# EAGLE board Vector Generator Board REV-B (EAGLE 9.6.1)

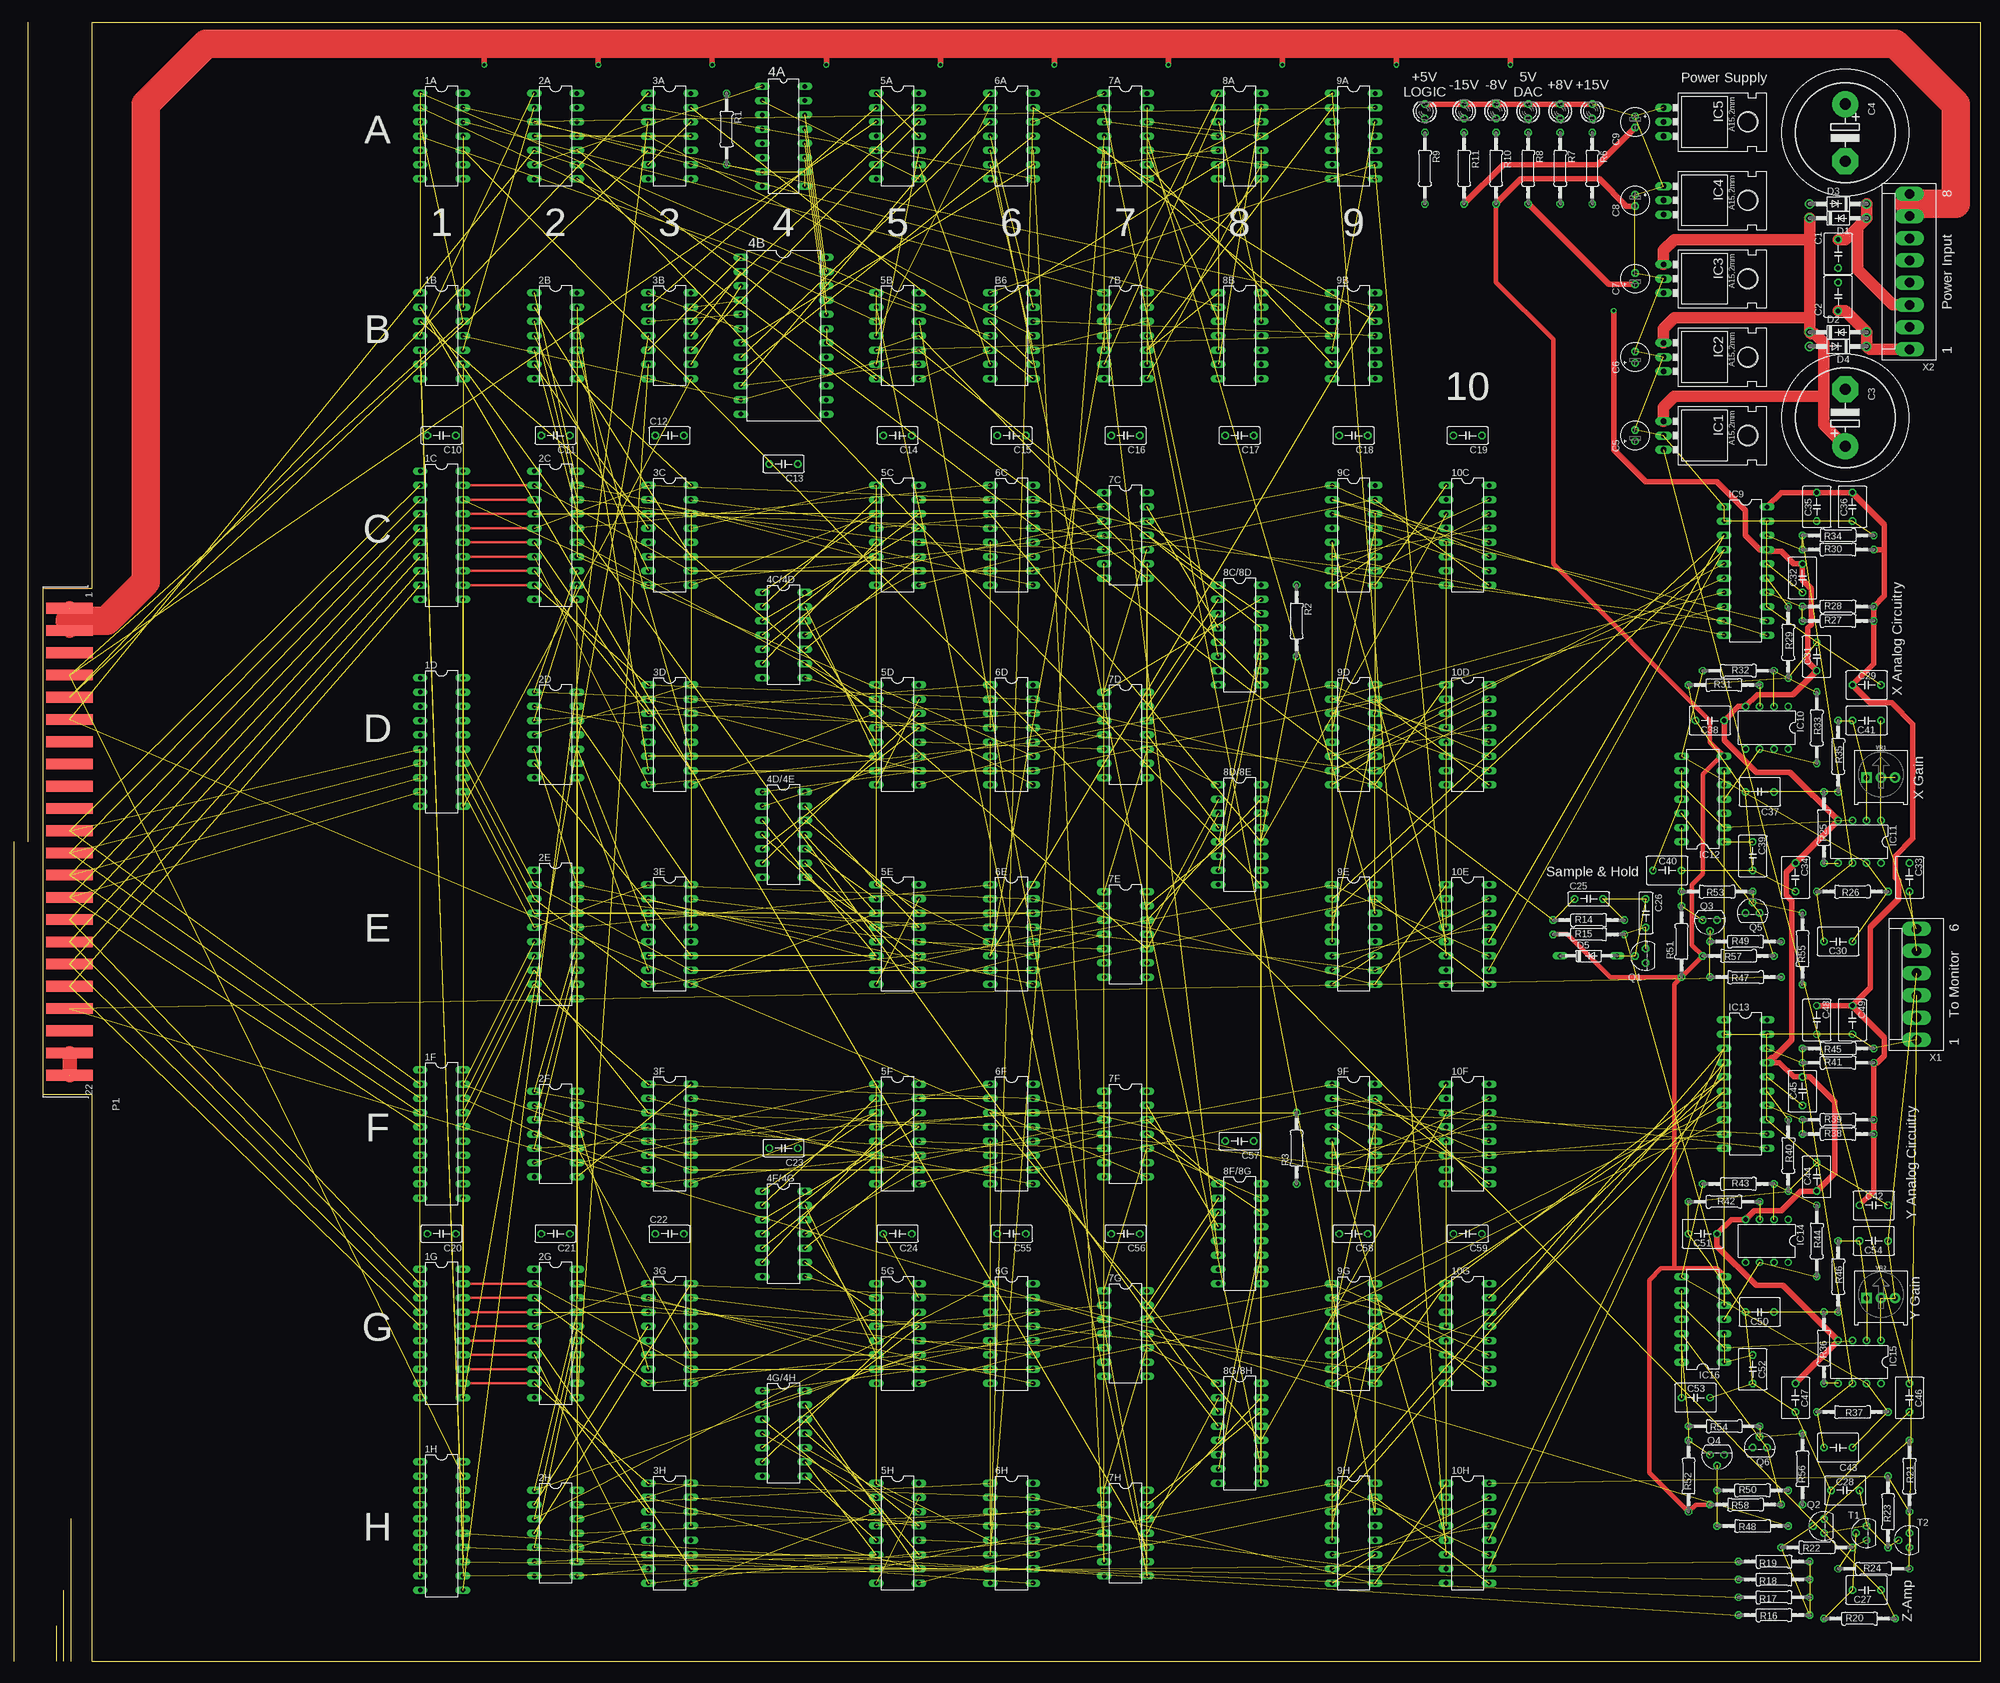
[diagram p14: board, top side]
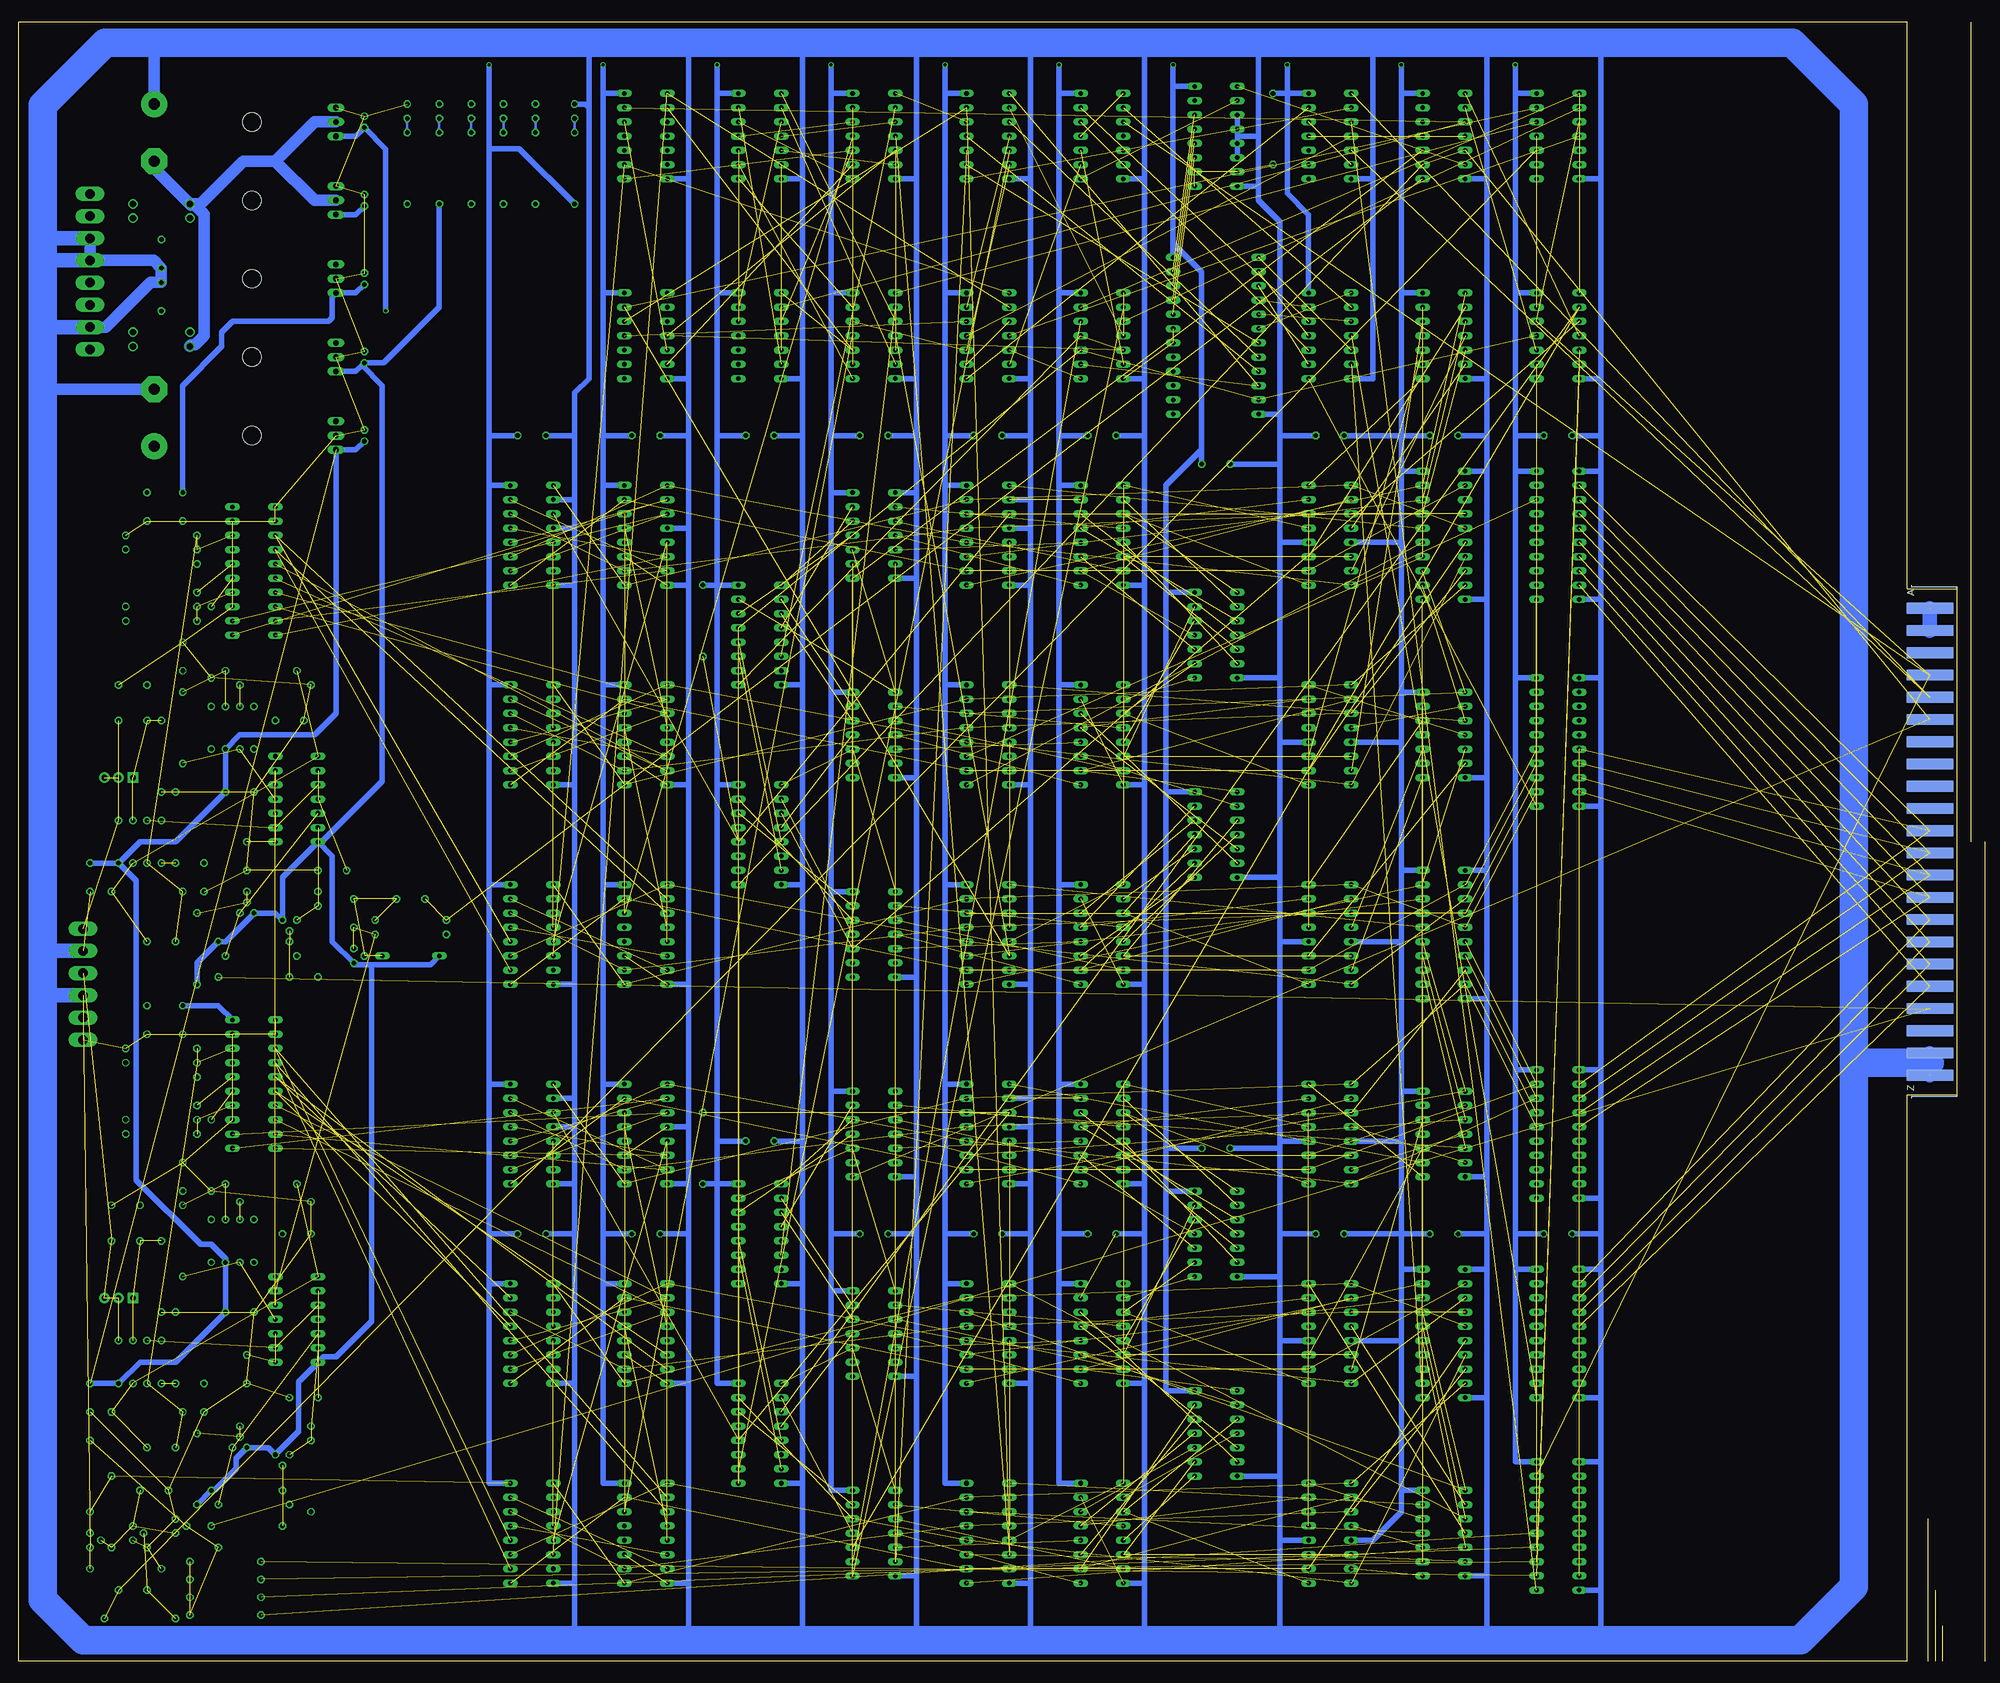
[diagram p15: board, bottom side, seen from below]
Size 350.52 x 292.1 mm. Coordinates in mm from the lower left corner, seen from the top.
Outline: 10.16,0 10.16,25.4
Outline: 8.89,0 8.89,12.7
Outline: 7.62,0 7.62,6.35
Outline: 0,0 0,146.05
Outline: 2.54,146.05 2.54,292.1
Outline: 13.97,0 13.97,100.97 5.08,100.97 5.08,191.13 13.97,191.13 13.97,292.1 350.52,292.1 350.52,0 13.97,0
Copper layers (1*16): Top 0.035mm / dielectric 1.5mm / Bottom 0.035mm
Design rules "default": minimum track width 6mil, minimum drill 0.35mm, track to track 6mil, track to pad 6mil, pad to pad 6mil, via to via 6mil, smd to smd 6mil, copper to edge 40mil, drill to drill 6mil, minimum pad ring 10mil, minimum via ring 8mil, stop-mask expansion 4mil, vias tented up to drill 0mil, thermal gap 10mil
Net classes: 0 default: width 0.406 mm, clearance 0.406 mm

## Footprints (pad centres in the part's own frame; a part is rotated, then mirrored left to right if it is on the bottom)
DIL14 = drill 0.813 long: 1 -7.62,-3.81; 2 -5.08,-3.81; 3 -2.54,-3.81; 4 0,-3.81; 5 2.54,-3.81; 6 5.08,-3.81; 7 7.62,-3.81; 8 7.62,3.81; 9 5.08,3.81; 10 2.54,3.81; 11 0,3.81; 12 -2.54,3.81; 13 -5.08,3.81; 14 -7.62,3.81
DIL20 = drill 0.813 long: 1 -11.43,-3.81; 2 -8.89,-3.81; 3 -6.35,-3.81; 4 -3.81,-3.81; 5 -1.27,-3.81; 6 1.27,-3.81; 7 3.81,-3.81; 8 6.35,-3.81; 9 8.89,-3.81; 10 11.43,-3.81; 11 11.43,3.81; 12 8.89,3.81; 13 6.35,3.81; 14 3.81,3.81; 15 1.27,3.81; 16 -1.27,3.81; 17 -3.81,3.81; 18 -6.35,3.81; 19 -8.89,3.81; 20 -11.43,3.81
DIL16 = drill 0.813 long: 1 -8.89,-3.81; 2 -6.35,-3.81; 3 -3.81,-3.81; 4 -1.27,-3.81; 5 1.27,-3.81; 6 3.81,-3.81; 7 6.35,-3.81; 8 8.89,-3.81; 9 8.89,3.81; 10 6.35,3.81; 11 3.81,3.81; 12 1.27,3.81; 13 -1.27,3.81; 14 -3.81,3.81; 15 -6.35,3.81; 16 -8.89,3.81
DIL24-6 = drill 0.813 long: 1 -13.97,-7.62; 2 -11.43,-7.62; 3 -8.89,-7.62; 4 -6.35,-7.62; 5 -3.81,-7.62; 6 -1.27,-7.62; 7 1.27,-7.62; 8 3.81,-7.62; 9 6.35,-7.62; 10 8.89,-7.62; 11 11.43,-7.62; 12 13.97,-7.62; 13 13.97,7.62; 14 11.43,7.62; 15 8.89,7.62; 16 6.35,7.62; 17 3.81,7.62; 18 1.27,7.62; 19 -1.27,7.62; 20 -3.81,7.62; 21 -6.35,7.62; 22 -8.89,7.62; 23 -11.43,7.62; 24 -13.97,7.62
C050-050X075 = drill 0.813 octagon: 1 -2.54,0; 2 2.54,0
EB22,5D = drill 2.007 pad 4.597: + -5.08,0 | drill 2.007 pad 4.597 octagon: - 5.08,0
E2-5 = drill 0.813 pad 1.27: + -1.016,0 | drill 0.813 pad 1.27 octagon: - 1.016,0
C050-030X075 = drill 0.813 octagon: 1 -2.54,0; 2 2.54,0
C050-025X075 = drill 0.813 octagon: 1 -2.54,0; 2 2.54,0
DO41-10 = drill 1.118: A 5.08,0; C -5.08,0
DO35-10 = drill 0.813 long: A 5.08,0; C -5.08,0
78XXL = drill 1.016 long: GND 0,-3.81; IN -2.54,-3.81; OUT 2.54,-3.81 | hole 3.302: 0,11.176
79XXL = drill 1.016 long: GND -2.54,-3.81; IN 0,-3.81; OUT 2.54,-3.81 | hole 3.302: 0,11.176
DIL08 = drill 0.813 pad 1.27: 1 -3.81,-3.81; 2 -1.27,-3.81; 3 1.27,-3.81; 4 3.81,-3.81; 5 3.81,3.81; 6 1.27,3.81; 7 -1.27,3.81; 8 -3.81,3.81
LED3MM = drill 0.813 octagon: A -1.27,0; K 1.27,0
44PINEDGE = smd 1.905 x 8.255: 1 -41.605,4.826; 2 -37.643,4.826; 3 -33.68,4.826; 4 -29.718,4.826; 5 -25.756,4.826; 6 -21.793,4.826; 7 -17.831,4.826; 8 -13.868,4.826; 9 -9.906,4.826; 10 -5.944,4.826; 11 -1.981,4.826; 12 1.981,4.826; 13 5.944,4.826; 14 9.906,4.826; 15 13.868,4.826; 16 17.831,4.826; 17 21.793,4.826; 18 25.756,4.826; 19 29.718,4.826; 20 33.68,4.826; 21 37.643,4.826; 22 41.605,4.826 | smd 1.905 x 8.255 bottom: A -41.605,4.826; B -37.643,4.826; C -33.68,4.826; D -29.718,4.826; E -25.756,4.826; F -21.793,4.826; H -17.831,4.826; J -13.868,4.826; K -9.906,4.826; L -5.944,4.826; M -1.981,4.826; N 1.981,4.826; P 5.944,4.826; R 9.906,4.826; S 13.868,4.826; T 17.831,4.826; U 21.793,4.826; V 25.756,4.826; W 29.718,4.826; X 33.68,4.826; Y 37.643,4.826; Z 41.605,4.826
TO92 = drill 0.813 octagon: 1 1.27,0; 2 0,1.905; 3 -1.27,0
0207/12 = drill 0.813 octagon: 1 -6.35,0; 2 6.35,0
TRIMPOT-PTH-3386U = drill 1.016 pad 1.88 square: 1 -2.54,-0.015 | drill 1.016 pad 1.88: 2 0,-0.015; 3 2.54,-0.015
KK-156-6 = drill 1.7 pad 2.184 long: 1 -9.9,0; 2 -5.94,0; 3 -1.98,0; 4 1.98,0; 5 5.94,0; 6 9.9,0
KK-156-8 = drill 1.7 pad 2.184 long: 1 -13.86,0; 2 -9.9,0; 3 -5.94,0; 4 -1.98,0; 5 1.98,0; 6 5.94,0; 7 9.9,0; 8 13.86,0

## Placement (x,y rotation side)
1A  7404N  [DIL14]  76.2,271.78 270 top
1B  7402N  [DIL14]  76.2,236.22 270 top
1C  74HC573N  [DIL20]  76.2,200.66 270 top
1D  74HC573N  [DIL20]  76.2,163.83 270 top
1F  74HC573N  [DIL20]  76.2,93.98 270 top
1G  74HC573N  [DIL20]  76.2,58.42 270 top
1H  74HC573N  [DIL20]  76.2,24.13 270 top
2A  7400N  [DIL14]  96.52,271.78 270 top
2B  7404N  [DIL14]  96.52,236.22 270 top
2C  74HC573N  [DIL20]  96.52,200.66 270 top
2D  7404N  [DIL14]  96.52,165.1 270 top
2E  74HC573N  [DIL20]  96.52,129.54 270 top
2F  7404N  [DIL14]  96.52,93.98 270 top
2G  74HC573N  [DIL20]  96.52,58.42 270 top
2H  7404N  [DIL14]  96.52,22.86 270 top
3A  7432N  [DIL14]  116.84,271.78 270 top
3B  7404N  [DIL14]  116.84,236.22 270 top
3C  7483N  [DIL16]  116.84,200.66 270 top
3D  7483N  [DIL16]  116.84,165.1 270 top
3E  7483N  [DIL16]  116.84,129.54 270 top
3F  7483N  [DIL16]  116.84,93.98 270 top
3G  7483N  [DIL16]  116.84,58.42 270 top
3H  7483N  [DIL16]  116.84,22.86 270 top
4A  74161N  [DIL16]  137.16,271.78 270 top
4B  74154N  [DIL24-6]  137.16,236.22 270 top
4C/4D  7404N  [DIL14]  137.16,182.88 270 top
4D/4E  7404N  [DIL14]  137.16,147.32 270 top
4F/4G  7404N  [DIL14]  137.16,76.2 270 top
4G/4H  7404N  [DIL14]  137.16,40.64 270 top
5A  7432N  [DIL14]  157.48,271.78 270 top
5B  74S11N  [DIL14]  157.48,236.22 270 top
5C  74157N  [DIL16]  157.48,200.66 270 top
5D  74157N  [DIL16]  157.48,165.1 270 top
5E  74157N  [DIL16]  157.48,129.54 270 top
5F  74157N  [DIL16]  157.48,93.98 270 top
5G  74157N  [DIL16]  157.48,58.42 270 top
5H  74157N  [DIL16]  157.48,22.86 270 top
6A  7404N  [DIL14]  177.8,271.78 270 top
6C  7485N  [DIL16]  177.8,200.66 270 top
6D  7485N  [DIL16]  177.8,165.1 270 top
6E  7485N  [DIL16]  177.8,129.54 270 top
6F  7485N  [DIL16]  177.8,93.98 270 top
6G  7485N  [DIL16]  177.8,58.42 270 top
6H  7485N  [DIL16]  177.8,22.86 270 top
7A  74S08N  [DIL14]  198.12,271.78 270 top
7B  74S08N  [DIL14]  198.12,236.22 270 top
7C  7495N  [DIL14]  198.12,200.66 270 top
7D  7495N  [DIL14]  198.12,165.1 270 top
7E  7495N  [DIL14]  198.12,129.54 270 top
7F  7495N  [DIL14]  198.12,93.98 270 top
7G  7495N  [DIL14]  198.12,58.42 270 top
7H  7495N  [DIL14]  198.12,22.86 270 top
8A  7432N  [DIL14]  218.44,271.78 270 top
8B  74S11N  [DIL14]  218.44,236.22 270 top
8C/8D  7497N  [DIL16]  218.44,182.88 270 top
8D/8E  7497N  [DIL16]  218.44,147.32 270 top
8F/8G  7497N  [DIL16]  218.44,76.2 270 top
8G/8H  7497N  [DIL16]  218.44,40.64 270 top
9A  7404N  [DIL14]  238.76,271.78 270 top
9B  74S08N  [DIL14]  238.76,236.22 270 top
9C  74191N  [DIL16]  238.76,200.66 270 top
9D  74191N  [DIL16]  238.76,165.1 270 top
9E  74191N  [DIL16]  238.76,129.54 270 top
9F  74191N  [DIL16]  238.76,93.98 270 top
9G  74191N  [DIL16]  238.76,58.42 270 top
9H  74191N  [DIL16]  238.76,22.86 270 top
10C  7485N  [DIL16]  259.08,200.66 270 top
10D  7485N  [DIL16]  259.08,165.1 270 top
10E  7485N  [DIL16]  259.08,129.54 270 top
10F  7485N  [DIL16]  259.08,93.98 270 top
10G  7485N  [DIL16]  259.08,58.42 270 top
10H  7485N  [DIL16]  259.08,22.86 270 top
B6  74S08N  [DIL14]  177.8,236.22 270 top
C1  .1 uf  [C050-050X075]  325.12,250.82 270 top
C2  .1 uf  [C050-050X075]  325.12,243.21 90 top
C3  470 uf  [EB22,5D]  326.39,221.62 90 top
C4  470 uf  [EB22,5D]  326.39,272.41 270 top
C5  1 uf  [E2-5]  288.93,218.44 90 top
C6  1uf  [E2-5]  288.93,232.41 90 top
C7  1 uf  [E2-5]  288.93,246.38 90 top
C8  1uf  [E2-5]  288.93,260.35 270 top
C9  1 uf  [E2-5]  288.93,274.32 270 top
C10  .1uf  [C050-030X075]  76.2,218.44 180 top
C11  .1uf  [C050-030X075]  96.52,218.44 180 top
C12  .1uf  [C050-030X075]  116.84,218.44 0 top
C13  .1uf  [C050-030X075]  137.16,213.36 180 top
C14  .1uf  [C050-030X075]  157.48,218.44 180 top
C15  .1uf  [C050-030X075]  177.8,218.44 180 top
C16  .1uf  [C050-030X075]  198.12,218.44 180 top
C17  .1uf  [C050-030X075]  218.44,218.44 180 top
C18  .1uf  [C050-030X075]  238.76,218.44 180 top
C19  .1uf  [C050-030X075]  259.08,218.44 180 top
C20  .1uf  [C050-030X075]  76.2,76.2 180 top
C21  .1uf  [C050-030X075]  96.52,76.2 180 top
C22  .1uf  [C050-030X075]  116.84,76.2 0 top
C23  .1uf  [C050-030X075]  137.16,91.44 180 top
C24  .1uf  [C050-030X075]  157.48,76.2 180 top
C25  390pf  [C050-025X075]  280.67,135.89 0 top
C26  100pf  [C050-025X075]  290.83,133.35 270 top
C27  270pf  [C050-050X075]  330.2,12.7 180 top
C28  .01uf  [C050-050X075]  326.39,30.48 180 top
C29  .1uf  [C050-050X075]  330.2,173.99 0 top
C30  10pf  [C050-050X075]  325.12,128.27 180 top
C31  .1uf  [C050-050X075]  321.31,179.07 90 top
C32  .01uf  [C050-050X075]  318.77,193.04 90 top
C33  .1uf  [C050-050X075]  337.82,139.7 270 top
C34  .1uf  [C050-050X075]  317.5,139.7 270 top
C35  .1uf  [C050-050X075]  321.31,205.74 270 top
C36  .1uf  [C050-050X075]  327.66,205.74 270 top
C37  .1uf  [C050-050X075]  311.15,154.94 180 top
C38  .1uf  [C050-050X075]  302.26,167.64 180 top
C39  220pf  [C050-050X075]  309.88,143.51 270 top
C40  220pf  [C050-050X075]  294.64,140.97 0 top
C41  69pf  [C050-050X075]  330.2,167.64 180 top
C42  .1uf  [C050-050X075]  331.47,81.28 0 top
C43  10pf  [C050-050X075]  325.12,38.1 180 top
C44  .1uf  [C050-050X075]  321.31,86.36 90 top
C45  .01uf  [C050-050X075]  318.77,101.6 90 top
C46  .1uf  [C050-050X075]  337.82,46.99 270 top
C47  .1uf  [C050-050X075]  317.5,46.99 270 top
C48  .1uf  [C050-050X075]  321.31,114.3 270 top
C49  .1uf  [C050-050X075]  327.66,114.3 270 top
C50  .1uf  [C050-050X075]  311.15,62.23 180 top
C51  .1uf  [C050-050X075]  300.99,76.2 180 top
C52  220pf  [C050-050X075]  309.88,52.07 270 top
C53  220pf  [C050-050X075]  299.72,46.99 0 top
C54  69pf  [C050-050X075]  331.47,74.93 180 top
C55  .1uf  [C050-030X075]  177.8,76.2 180 top
C56  .1uf  [C050-030X075]  198.12,76.2 180 top
C57  .1uf  [C050-030X075]  218.44,92.71 180 top
C58  .1uf  [C050-030X075]  238.76,76.2 180 top
C59  .1uf  [C050-030X075]  259.08,76.2 180 top
D1  1N4004  [DO41-10]  325.12,257.18 0 top
D2  1N4004  [DO41-10]  325.12,236.85 0 top
D3  1N4004  [DO41-10]  325.12,259.72 180 top
D4  1N4004  [DO41-10]  325.12,234.31 180 top
D5  1N4148  [DO35-10]  280.67,125.73 0 top
IC1  7815  [78XXL]  297.81,218.44 270 top
IC2  7808  [78XXL]  297.81,232.41 270 top
IC3  7805  [78XXL]  297.81,246.38 270 top
IC4  7908  [79XXL]  297.81,260.35 270 top
IC5  7915  [79XXL]  297.81,274.32 270 top
IC9  DAC312  [DIL20]  308.61,194.31 270 top
IC10  TL081P  [DIL08]  312.42,166.37 180 top
IC11  TL082P  [DIL08]  328.93,146.05 180 top
IC12  4016N  [DIL14]  300.99,153.67 90 top
IC13  DAC312  [DIL20]  308.61,102.87 270 top
IC14  TL081P  [DIL08]  312.42,74.93 180 top
IC15  TL082P  [DIL08]  328.93,53.34 180 top
IC16  4016N  [DIL14]  300.99,60.96 90 top
LED1  [LED3MM]  281.31,276.23 90 top
LED2  [LED3MM]  275.59,276.23 90 top
LED3  [LED3MM]  269.88,276.23 90 top
LED4  [LED3MM]  251.46,276.23 90 top
LED5  [LED3MM]  264.16,276.23 270 top
LED6  [LED3MM]  258.44,276.23 270 top
P1  44PINEDGE  [44PINEDGE]  5.08,146.05 270 top
Q1  2N3906  [TO92]  290.83,125.73 90 top
Q2  2N3906  [TO92]  322.58,24.13 90 top
Q3  2N3906  [TO92]  302.26,132.08 180 top
Q4  2N3906  [TO92]  303.53,36.83 180 top
Q5  2N3906  [TO92]  309.88,133.35 0 top
Q6  2N3906  [TO92]  311.15,38.1 0 top
R1  1K  [0207/12]  127,273.05 270 top
R2  1K  [0207/12]  228.6,185.42 270 top
R3  1K  [0207/12]  228.6,91.44 90 top
R6  680  [0207/12]  281.31,266.06 270 top
R7  330  [0207/12]  275.59,266.06 270 top
R8  150  [0207/12]  269.88,266.06 270 top
R9  150  [0207/12]  251.46,266.06 270 top
R10  330  [0207/12]  264.16,266.06 270 top
R11  680  [0207/12]  258.44,266.06 270 top
R14  47K  [0207/12]  280.67,132.08 0 top
R15  330  [0207/12]  280.67,129.54 0 top
R16  1.2K  [0207/12]  313.69,8.26 0 top
R17  2.2K  [0207/12]  313.69,11.43 0 top
R18  4.7K  [0207/12]  313.69,14.61 0 top
R19  10K  [0207/12]  313.69,17.78 0 top
R20  1K  [0207/12]  328.93,7.62 0 top
R21  3.9K  [0207/12]  337.82,33.02 270 top
R22  22K  [0207/12]  321.31,20.32 180 top
R23  68  [0207/12]  334.01,26.67 90 top
R24  27  [0207/12]  331.47,16.51 0 top
R25  6.8K  [0207/12]  322.58,148.59 270 top
R26  8.2K  [0207/12]  327.66,137.16 180 top
R27  10k  [0207/12]  325.12,185.42 0 top
R28  10k  [0207/12]  325.12,187.96 0 top
R29  4.7K  [0207/12]  316.23,181.61 270 top
R30  10K  [0207/12]  325.12,198.12 0 top
R31  4.7K  [0207/12]  304.8,173.99 0 top
R32  10K  [0207/12]  307.34,176.53 0 top
R33  10K  [0207/12]  321.31,166.37 270 top
R34  2.2K  [0207/12]  325.12,200.66 180 top
R35  3.9K  [0207/12]  325.12,161.29 270 top
R36  6.8K  [0207/12]  322.58,55.88 270 top
R37  8.2K  [0207/12]  327.66,44.45 180 top
R38  10k  [0207/12]  325.12,93.98 0 top
R39  10k  [0207/12]  325.12,96.52 0 top
R40  4.7K  [0207/12]  316.23,90.17 270 top
R41  10K  [0207/12]  325.12,106.68 0 top
R42  4.7K  [0207/12]  304.8,81.91 0 top
R43  10K  [0207/12]  307.34,85.09 0 top
R44  10K  [0207/12]  321.31,74.93 270 top
R45  2.2K  [0207/12]  325.12,109.22 180 top
R46  3.9K  [0207/12]  325.12,68.58 270 top
R47  18K  [0207/12]  308.61,121.92 180 top
R48  18K  [0207/12]  309.88,24.13 180 top
R49  2.2K  [0207/12]  308.61,128.27 0 top
R50  2.2K  [0207/12]  309.88,30.48 0 top
R51  3.3K  [0207/12]  297.18,128.27 90 top
R52  3.3K  [0207/12]  298.45,33.02 90 top
R53  100K  [0207/12]  303.53,137.16 180 top
R54  100K  [0207/12]  304.8,41.91 180 top
R55  4.7K  [0207/12]  318.77,127 90 top
R56  4.7K  [0207/12]  318.77,34.29 90 top
R57  56K  [0207/12]  307.34,125.73 180 top
R58  56K  [0207/12]  308.61,27.94 180 top
T1  2N3904  [TO92]  330.2,22.86 90 top
T2  2N3904  [TO92]  337.82,21.59 90 top
VR1  10k  [TRIMPOT-PTH-3386U]  332.74,157.48 0 top
VR2  10k  [TRIMPOT-PTH-3386U]  332.74,64.77 0 top
X1  [KK-156-6]  339.09,120.65 90 top
X2  [KK-156-8]  337.82,247.65 90 top

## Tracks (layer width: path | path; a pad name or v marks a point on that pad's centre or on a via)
1DX0  (2 unrouted)
1DX1  (2 unrouted)
1DX2  (2 unrouted)
1DX3  (2 unrouted)
1DX4  (2 unrouted)
1DX5  (2 unrouted)
1DX6  (2 unrouted)
1DX7  (2 unrouted)
1DX8  (2 unrouted)
1DX9  (2 unrouted)
1DX10  (2 unrouted)
1DX11  (2 unrouted)
1DY0  (2 unrouted)
1DY1  (2 unrouted)
1DY2  (2 unrouted)
1DY3  (2 unrouted)
1DY4  (2 unrouted)
1DY5  (2 unrouted)
1DY6  (2 unrouted)
1DY7  (2 unrouted)
1DY8  (2 unrouted)
1DY9  (2 unrouted)
1DY10  (2 unrouted)
1DY11  (2 unrouted)
2.5MHZ  (11 unrouted)
5MHZ  (8 unrouted)
36VAC_A
  Top 2.032: D3.C D1.A 328.61,255.59 | C1.1 326.39,253.37 328.61,255.59 | X2.3 334.87,241.71 328.61,247.97 328.61,255.59
36VAC_B
  Top 2.032: X2.1 330.72,233.79 D4.C D2.A 326.39,240.66 C2.1
+5V_DAC
  Top 1.016: C7.+ 284.23,245.36 R8.2 | IC9.20 314.96,208.28 C35.1 C36.1 333.38,202.56 333.38,198.12 | 333.38,198.12 R30.2 | 333.38,198.12 333.38,189.87 R28.2 R27.2 331.47,177.8 C29.1 330.83,170.81 334.64,170.81 338.45,167 338.45,146.69 335.28,143.51 335.28,139.7 335.92,139.06 335.92,135.89 330.83,130.81 330.83,120.02 C49.1 | C49.1 C48.1 | C49.1 333.38,111.12 333.38,107.95 332.11,106.68 R41.2 R39.2 R38.2 331.47,83.82 C42.1
  Bottom 1.016: C7.+ 290.45,243.84 IC3.OUT 294.64,243.21 294.64,239.4 295.27,238.76 312.42,238.76 314.32,236.85 314.32,234.31 321.31,227.33 C35.1 | IC13.20 314.96,116.84 C48.1
+8VDC
  Bottom 1.016: IC2.OUT 290.45,229.87 289.37,230.95 | 289.37,230.95 C6.+ 285.5,231.39 275.59,241.3 R7.2 | 289.37,230.95 285.75,227.33 285.75,156.84 296.55,146.05 IC12.14 | IC12.14 303.53,139.7 Q3.3 304.8,133.35 Q5.3 313.69,128.27 R49.2 318.77,124.46 R55.1 | IC12.14 294.64,143.51 294.64,128.27 Q1.3 290.83,124.16 287.65,124.16 | 287.65,124.16 277.17,124.16 D5.C | R56.1 R50.2 315.59,30.48 311.78,34.29 311.78,36.2 Q6.3 306.07,38.1 Q4.3 300.66,40.97 300.66,49.86 IC16.14 296.21,54.3 293.96,54.3 287.65,60.61 287.65,124.16
+15VDC  (1 unrouted)
  Bottom 1.016: C5.+ 290.45,215.9 IC1.OUT 294,168.91 297.81,165.1 311.15,165.1 IC10.7 C37.1 322.58,146.05 328.93,146.05 IC11.8 | IC11.8 C33.1 | IC11.8 329.56,139.06 329.56,85.72 318.13,74.3 316.23,74.3 313.69,71.75 IC14.7 C50.1 322.58,53.34 328.93,53.34 IC15.8 C46.1
+22VDC
  Top 2.032: D1.C 320.04,253.37 | 320.04,253.37 320.04,239.4 | 320.04,239.4 D2.C 320.32,236.58 320.98,236.58 322.58,234.97 322.58,225.43 | IC2.IN 294,237.49 295.91,239.4 320.04,239.4 | IC3.IN 294,251.46 295.91,253.37 320.04,253.37 | C3.+ 322.58,220.34 322.58,225.43 | IC1.IN 294,223.52 295.91,225.43 322.58,225.43
-8VDC
  Top 0.762: R58.2 299.72,27.94 R52.1 291.46,33.66 291.46,67.94 293.55,70.03 295.91,70.03 | IC16.7 304.8,68.75 303.52,70.03 295.91,70.03 | 295.91,70.03 295.91,120.65 R51.1 | R51.1 R57.2 299.08,127.64 299.08,138.43 300.99,140.34 300.99,158.12 304.17,161.29 IC12.7 302.26,163.83 302.26,167.64 274.32,195.58 274.32,235.59 264.16,245.75 R10.2 | R15.1 276.86,129.54 284.48,121.92 R51.1
  Top 1.016: C8.- 287.4,259.33 282.57,264.16 268.61,264.16 R10.2
  Bottom 1.016: IC4.OUT 290.45,257.81 C8.-
-15VDC  (via drill 0.55)
  Top 1.016: C9.- 282.32,266.7 265.43,266.7 R11.2 | C47.1 IC15.4 315.26,67 310.5,67 303.53,73.97 C51.1 306.07,78.74 IC14.4 310.21,80.34 314.98,80.34 318.46,83.82 C44.1 324.49,87 324.49,99.69 320.04,104.14 C45.2 317.21,104.14 314.67,106.68 IC13.17 313.38,107.65 313.73,107.65 316.87,110.78 316.87,135.57 315.93,136.51 315.93,140.67 C34.1 IC11.4 316.53,158.44 310.5,158.44 304.8,164.14 C38.1 307.34,170.18 IC10.4 310.68,172.25 317.03,172.25 C31.1 319.74,178.1 319.74,184.16 320.34,184.77 320.34,191.15 318.77,192.73 C32.2 317.21,195.58 315,197.79 312.75,197.79 IC9.17 311.15,198.12 308.61,200.66 308.61,205.1 303.53,210.19 290.83,210.19 285.12,215.9 v285.12,240.66
  Bottom 1.016: IC5.OUT 290.45,271.78 C9.- 285.12,269.49 v285.12,240.66
/1DX0  (1 unrouted)
/1DX1  (1 unrouted)
/1DX2  (1 unrouted)
/1DX3  (1 unrouted)
/1DX4  (1 unrouted)
/1DX5  (1 unrouted)
/1DX6  (1 unrouted)
/1DX7  (1 unrouted)
/1DX8  (1 unrouted)
/1DX9  (1 unrouted)
/1DX10  (1 unrouted)
/1DX11  (1 unrouted)
/1DY0  (1 unrouted)
/1DY1  (1 unrouted)
/1DY2  (1 unrouted)
/1DY3  (1 unrouted)
/1DY4  (1 unrouted)
/1DY5  (1 unrouted)
/1DY6  (1 unrouted)
/1DY7  (1 unrouted)
/1DY8  (1 unrouted)
/1DY9  (1 unrouted)
/1DY10  (1 unrouted)
/1DY11  (1 unrouted)
/COUNT  (11 unrouted)
/DX=0  (1 unrouted)
/DY=0  (1 unrouted)
/FRAMECOMPLETE  (1 unrouted)
/HALTROTATE  (2 unrouted)
/INHIBITX  (2 unrouted)
/INHIBITY  (2 unrouted)
/LDROT  (1 unrouted)
/LDX2  (1 unrouted)
/LDXY1  (1 unrouted)
/LDY2  (1 unrouted)
/LDZ  (1 unrouted)
/ROTATE  (2 unrouted)
/SUBTRACT  (1 unrouted)
/TTLINVX  (1 unrouted)
/TTLINVY  (1 unrouted)
/VRAMPC1  (1 unrouted)
/VRAMPC2  (1 unrouted)
/VRAMPC3  (1 unrouted)
/XCUR0  (1 unrouted)
/XCUR1  (1 unrouted)
/XCUR2  (1 unrouted)
/XCUR3  (1 unrouted)
/XCUR4  (1 unrouted)
/XCUR5  (1 unrouted)
/XCUR6  (1 unrouted)
/XCUR7  (1 unrouted)
/XCUR8  (1 unrouted)
/XCUR9  (1 unrouted)
/XCUR10  (1 unrouted)
/XCUR11  (1 unrouted)
/YCUR0  (1 unrouted)
/YCUR1  (1 unrouted)
/YCUR2  (1 unrouted)
/YCUR3  (1 unrouted)
/YCUR4  (1 unrouted)
/YCUR5  (1 unrouted)
/YCUR6  (1 unrouted)
/YCUR7  (1 unrouted)
/YCUR8  (1 unrouted)
/YCUR9  (1 unrouted)
/YCUR10  (1 unrouted)
/YCUR11  (1 unrouted)
A  (5 unrouted)
B  (5 unrouted)
BEAMOFF  (1 unrouted)
BEAMON  (3 unrouted)
COUNT  (3 unrouted)
DACX0  (2 unrouted)
DACX1  (2 unrouted)
DACX2  (2 unrouted)
DACX3  (2 unrouted)
DACX4  (2 unrouted)
DACX5  (2 unrouted)
DACX6  (2 unrouted)
DACX7  (2 unrouted)
DACX8  (2 unrouted)
DACX9  (2 unrouted)
DACX10  (1 unrouted)
DACX11  (1 unrouted)
DACY0  (2 unrouted)
DACY1  (2 unrouted)
DACY2  (2 unrouted)
DACY3  (2 unrouted)
DACY4  (2 unrouted)
DACY5  (2 unrouted)
DACY6  (2 unrouted)
DACY7  (2 unrouted)
DACY8  (2 unrouted)
DACY9  (2 unrouted)
DACY10  (1 unrouted)
DACY11  (1 unrouted)
DX0  (1 unrouted)
DX1  (1 unrouted)
DX2  (1 unrouted)
DX3  (1 unrouted)
DX4  (1 unrouted)
DX5  (1 unrouted)
DX6  (1 unrouted)
DX7  (1 unrouted)
DX8  (1 unrouted)
DX9  (1 unrouted)
DX10  (1 unrouted)
DX11  (1 unrouted)
DX=0  (3 unrouted)
DY0  (1 unrouted)
DY1  (1 unrouted)
DY2  (1 unrouted)
DY3  (1 unrouted)
DY4  (1 unrouted)
DY5  (1 unrouted)
DY6  (1 unrouted)
DY7  (1 unrouted)
DY8  (1 unrouted)
DY9  (1 unrouted)
DY10  (1 unrouted)
DY11  (1 unrouted)
DY/DX=0  (1 unrouted)
DY=0  (3 unrouted)
FRAMECOMPLETE  (3 unrouted)
GND  (70 unrouted)
  Top 1.016: LED4.K LED6.A LED5.A LED3.K LED2.K LED1.K
  Top 2.54: P1.21 P1.22
  Bottom 1.016: 1H.10 68.58,12.7 | 68.58,3.81 68.58,12.7 | 68.58,12.7 68.58,35.56 | 68.58,35.56 68.58,46.99 | 68.58,46.99 68.58,69.85 | 68.58,69.85 68.58,76.2 | 68.58,76.2 68.58,82.55 | 68.58,82.55 68.58,105.41 | 68.58,105.41 68.58,152.4 | 68.58,152.4 68.58,175.26 | 68.58,175.26 68.58,189.23 | 68.58,189.23 68.58,212.09 | 68.58,212.09 68.58,218.44 | 68.58,218.44 68.58,228.6 | 68.58,228.6 68.58,264.16 | 68.58,264.16 68.58,288.47 | 68.58,46.99 1G.10 | 1F.10 68.58,82.55 | 1D.10 68.58,152.4 | 1C.10 68.58,189.23 | 1B.7 68.58,228.6 | 1A.7 68.58,264.16 | 2A.7 88.9,264.16 | 88.9,264.16 88.9,288.47 | 88.9,264.16 88.9,228.6 | 88.9,228.6 2B.7 | 88.9,228.6 88.9,218.44 | 88.9,218.44 88.9,212.09 | 88.9,212.09 88.9,189.23 | 88.9,189.23 2C.10 | 88.9,189.23 88.9,157.48 | 88.9,157.48 2D.7 | 88.9,157.48 88.9,140.97 | 88.9,140.97 2E.1 | 88.9,140.97 88.9,118.11 | 88.9,118.11 2E.10 | 88.9,118.11 88.9,86.36 | 88.9,86.36 2F.7 | 88.9,86.36 88.9,76.2 | 88.9,76.2 88.9,69.85 | 88.9,69.85 2G.1 | 88.9,69.85 88.9,46.99 | 88.9,46.99 2G.10 | 88.9,46.99 88.9,15.24 | 2H.7 88.9,15.24 | 88.9,15.24 88.9,3.81 | 68.58,35.56 1H.1 | 68.58,69.85 1G.1 | C20.2 68.58,76.2 | 88.9,76.2 C21.2 | 68.58,105.41 1F.1 | 68.58,175.26 1D.1 | 68.58,212.09 1C.1 | 68.58,218.44 C10.2 | 88.9,218.44 C11.2 | 88.9,212.09 2C.1 | 4B.12 125.73,222.25 | 125.73,222.25 125.73,218.44 | 125.73,218.44 125.73,213.36 | 125.73,213.36 125.73,199.39 | 125.73,199.39 125.73,175.26 | 125.73,175.26 125.73,163.83 | 125.73,163.83 125.73,139.7 | 125.73,139.7 125.73,128.27 | 125.73,128.27 125.73,92.71 | 125.73,92.71 125.73,91.44 | 125.73,91.44 125.73,76.2 | 125.73,76.2 125.73,68.58 | 125.73,68.58 125.73,57.15 | 125.73,57.15 125.73,33.02 | 125.73,33.02 125.73,21.59 | 125.73,21.59 125.73,3.81
  Bottom 1.016: 125.73,222.25 125.73,256.54 129.54,260.35 129.54,262.89 | 129.54,262.89 129.54,271.78 | 129.54,271.78 129.54,288.47 | 4A.8 129.54,262.89 | 4A.3 4A.4 133.35,271.78 | 133.35,271.78 4A.5 4A.6 | 133.35,271.78 129.54,271.78 | 125.73,218.44 C12.2 | 125.73,213.36 C13.2 | 125.73,199.39 3C.12 | 125.73,163.83 3D.12 | 3E.12 125.73,128.27 | 125.73,139.7 4D/4E.7 | 125.73,175.26 4C/4D.7 | 125.73,92.71 3F.12 | 125.73,91.44 C23.2 | 125.73,68.58 4F/4G.7 | 125.73,57.15 3G.12 | 125.73,33.02 4G/4H.7 | 125.73,21.59 3H.12 | 5H.8 149.86,13.97 | 149.86,13.97 149.86,3.81 | 149.86,13.97 149.86,49.53 | 149.86,49.53 149.86,76.2 | 149.86,76.2 149.86,85.09 | 149.86,85.09 149.86,120.65 | 149.86,120.65 149.86,156.21 | 149.86,156.21 149.86,191.77 | 149.86,191.77 149.86,218.44 | 149.86,218.44 149.86,228.6 | 149.86,228.6 149.86,264.16 | 149.86,264.16 149.86,288.47 149.86,289.56 | 149.86,264.16 5A.7 | 149.86,228.6 5B.7 | 149.86,218.44 C14.2 | 149.86,191.77 5C.8 | 149.86,156.21 5D.8 | 149.86,120.65 5E.8 | 149.86,85.09 5F.8 | 149.86,76.2 C24.2 | 149.86,49.53 5G.8 | 6H.8 170.18,13.97 | 170.18,13.97 170.18,3.81 | 170.18,13.97 170.18,49.53 | 170.18,49.53 170.18,76.2 | 170.18,76.2 170.18,85.09 | 170.18,85.09 170.18,95.25 | 170.18,95.25 170.18,100.33 | 170.18,100.33 170.18,120.65 | 170.18,120.65 170.18,156.21 | 170.18,156.21 170.18,191.77 | 170.18,191.77 170.18,201.93 | 170.18,201.93 170.18,207.01 | 170.18,207.01 170.18,218.44 | 170.18,218.44 170.18,228.6 | 170.18,228.6 170.18,264.16 | 6A.7 170.18,264.16 | 170.18,264.16 170.18,288.47 | 170.18,228.6 B6.7 | 170.18,218.44 C15.2 | 170.18,207.01 6C.2 | 170.18,201.93 6C.4 | 170.18,191.77 6C.8 | 170.18,156.21 6D.8 | 170.18,120.65 6E.8 | 170.18,85.09 6F.8 | 170.18,95.25 6F.4
  Bottom 1.016: 170.18,100.33 6F.2 | 170.18,49.53 6G.8 | 7H.7 190.5,15.24 | 190.5,15.24 190.5,3.81 | 190.5,15.24 190.5,50.8 | 190.5,50.8 190.5,76.2 | 190.5,76.2 190.5,86.36 | 190.5,86.36 190.5,121.92 | 190.5,121.92 190.5,157.48 | 190.5,157.48 190.5,193.04 | 190.5,193.04 190.5,208.28 | 190.5,208.28 190.5,218.44 | 190.5,218.44 190.5,228.6 | 190.5,228.6 190.5,264.16 | 190.5,264.16 190.5,288.47 | 190.5,264.16 7A.7 | 190.5,228.6 7B.7 | 190.5,218.44 C16.2 | 190.5,208.28 7C.1 | 190.5,193.04 7C.7 | 190.5,157.48 7D.7 | 190.5,121.92 7E.7 | 190.5,86.36 7F.7 | 190.5,76.2 C56.2 | 170.18,76.2 C55.2 | 190.5,50.8 7G.7 | 8G/8H.8 210.82,31.75 | 210.82,31.75 210.82,3.81 | 210.82,31.75 210.82,67.31 | 210.82,67.31 210.82,92.71 | 210.82,92.71 210.82,138.43 | 210.82,138.43 210.82,173.99 | 210.82,173.99 210.82,218.44 | 210.82,218.44 210.82,228.6 | 210.82,228.6 210.82,264.16 | 8A.7 210.82,264.16 | 210.82,264.16 210.82,288.47 | 210.82,228.6 8B.7 | 210.82,218.44 C17.2 | 210.82,173.99 8C/8D.8 | 210.82,138.43 8D/8E.8 | 210.82,92.71 C57.2 | 210.82,67.31 8F/8G.8 | 9H.8 231.14,13.97 | 231.14,13.97 231.14,3.81 | 231.14,13.97 231.14,49.53 | 231.14,49.53 231.14,76.2 | 231.14,76.2 231.14,85.09 | 231.14,85.09 231.14,95.25 | 231.14,95.25 231.14,120.65 | 231.14,120.65 231.14,156.21 | 231.14,156.21 231.14,191.77 | 231.14,191.77 231.14,201.93 | 231.14,201.93 231.14,218.44 | 231.14,218.44 231.14,228.6 | 231.14,228.6 231.14,264.16 | 231.14,264.16 231.14,288.47 | 231.14,264.16 9A.7 | 231.14,228.6 9B.7 | 231.14,218.44 C18.2 | 231.14,201.93 9C.4 | 231.14,191.77 9C.8 | 231.14,156.21 9D.8 | 231.14,120.65 9E.8 | 231.14,85.09 9F.8 | 231.14,95.25 9F.4 | 231.14,76.2 C58.2 | 231.14,49.53 9G.8 | 10H.8 251.46,13.97 | 251.46,13.97 251.46,3.81 | 248.92,276.86 248.92,228.6 251.46,226.06 251.46,218.44
  Bottom 1.016: 248.92,276.86 248.92,288.47 | 251.46,13.97 251.46,49.53 | 251.46,49.53 251.46,76.2 | 251.46,76.2 251.46,85.09 | 251.46,85.09 251.46,95.25 | 251.46,95.25 251.46,100.33 | 251.46,100.33 251.46,120.65 | 251.46,120.65 251.46,156.21 | 251.46,156.21 251.46,191.77 | 251.46,191.77 251.46,201.93 | 251.46,201.93 251.46,207.01 | 251.46,207.01 251.46,218.44 | LED4.K 249.56,277.5 248.92,276.86 | 251.46,218.44 C19.2 | 251.46,207.01 10C.2 | 251.46,201.93 10C.4 | 251.46,191.77 10C.8 | 251.46,156.21 10D.8 | 251.46,120.65 10E.8 | 251.46,85.09 10F.8 | 251.46,95.25 10F.4 | 251.46,100.33 10F.2 | 251.46,76.2 C59.2 | 251.46,49.53 10G.8 | 3B.7 109.22,228.6 109.22,264.16 | 109.22,264.16 109.22,287.2 110.49,288.47 | 3A.7 109.22,264.16 | C22.2 125.73,76.2
  Bottom 2.032: X2.2 335.02,237.75 327.02,245.75 C2.2 C1.2 326.46,249.63 X2.5 X2.6 | C4.+ 326.39,288.47 | C3.- 346.3,226.69
  Bottom 2.54: X1.5 346.3,126.59 346.71,127 | X1.3 346,118.67 346.71,119.38 | X2.6 345.89,253.59 346.3,254 | X2.5 345.59,249.63 346.3,248.92 | X2.2 345.29,237.75 346.3,238.76 | P1.21 9.91,106.68 P1.22
  Bottom 5.08: 346.3,118.97 346.3,126.59 346.3,226.69 346.3,238.76 346.3,248.92 346.3,254 346.3,277.27 335.1,288.47 326.39,288.47 248.92,288.47 231.14,288.47 210.82,288.47 190.5,288.47 170.18,288.47 149.86,288.47 129.54,288.47 110.49,288.47 88.9,288.47 68.58,288.47 34.47,288.47 23.49,277.5 23.49,106.68 | 346.3,118.97 346,118.67 | 346.3,118.97 346.3,11.02 339.09,3.81 251.46,3.81 231.14,3.81 210.82,3.81 190.5,3.81 170.18,3.81 149.86,3.81 125.73,3.81 88.9,3.81 68.58,3.81 33.02,3.81 23.49,13.34 23.49,106.68 | 9.91,106.68 23.49,106.68
  pour Top (isolate 0.381): 295.91,280.03 313.69,280.03 313.69,212.72 295.91,212.72
HALTROTATE  (1 unrouted)
INHIBITX  (2 unrouted)
INHIBITY  (2 unrouted)
INTENSITY0  (2 unrouted)
INTENSITY1  (2 unrouted)
INTENSITY2  (2 unrouted)
INTENSITY3  (2 unrouted)
INVX  (3 unrouted)
INVY  (3 unrouted)
LDX2  (2 unrouted)
LDXY1  (3 unrouted)
LDY2  (2 unrouted)
LDZ  (1 unrouted)
N$1  (1 unrouted)
N$2  (2 unrouted)
N$4  (6 unrouted)
N$6
  Bottom 0.406: LED1.A R6.1
N$8
  Bottom 0.406: LED3.A R8.1
N$9
  Bottom 0.406: R9.1 LED4.A
N$10  (1 unrouted)
N$11  (4 unrouted)
N$12  (4 unrouted)
N$13  (1 unrouted)
N$14  (2 unrouted)
N$15  (2 unrouted)
N$16  (2 unrouted)
N$17  (2 unrouted)
N$18  (2 unrouted)
N$19  (2 unrouted)
N$20  (1 unrouted)
N$21  (2 unrouted)
N$22  (1 unrouted)
N$23  (3 unrouted)
N$24  (1 unrouted)
N$25  (4 unrouted)
N$26  (1 unrouted)
N$27  (2 unrouted)
N$28  (2 unrouted)
N$29  (2 unrouted)
N$30  (2 unrouted)
N$31  (1 unrouted)
N$32  (2 unrouted)
N$33  (3 unrouted)
N$34  (1 unrouted)
N$35  (2 unrouted)
N$36  (2 unrouted)
N$37  (2 unrouted)
N$38  (2 unrouted)
N$39  (2 unrouted)
N$40  (1 unrouted)
N$41  (1 unrouted)
N$42  (1 unrouted)
N$43  (1 unrouted)
N$44  (1 unrouted)
N$45
  Bottom 0.406: R7.1 LED2.A
N$47  (1 unrouted)
N$48
  Bottom 0.406: R10.1 LED5.K
N$49  (1 unrouted)
N$52  (4 unrouted)
N$53  (1 unrouted)
N$58  (1 unrouted)
N$59  (1 unrouted)
N$60
  Bottom 2.032: IC4.IN 297.81,260.35 304.8,267.34 | 304.8,267.34 310.51,267.34 318.13,259.72 D3.A | 304.8,267.34 297.81,274.32 IC5.IN | D3.A 319.76,259.44 319.1,259.44 317.5,257.83 317.5,236.2 319.1,234.59 319.76,234.59 D4.A | D3.A 326.39,266.06 C4.-
N$61  (1 unrouted)
N$62  (1 unrouted)
N$63  (1 unrouted)
N$64  (1 unrouted)
N$65  (1 unrouted)
N$67  (1 unrouted)
N$68  (1 unrouted)
N$69  (1 unrouted)
N$72  (1 unrouted)
N$73  (1 unrouted)
N$74  (1 unrouted)
N$75  (1 unrouted)
N$79  (1 unrouted)
N$80  (1 unrouted)
N$81  (1 unrouted)
N$82  (1 unrouted)
N$83  (1 unrouted)
N$84  (1 unrouted)
N$85  (1 unrouted)
N$86  (1 unrouted)
N$87  (1 unrouted)
N$88  (1 unrouted)
N$89  (1 unrouted)
N$90  (1 unrouted)
N$91  (1 unrouted)
N$92  (1 unrouted)
N$97  (1 unrouted)
N$99  (1 unrouted)
N$101  (1 unrouted)
N$102  (1 unrouted)
N$104  (1 unrouted)
N$111  (1 unrouted)
N$112  (1 unrouted)
N$113  (1 unrouted)
N$114  (1 unrouted)
N$115  (2 unrouted)
N$116  (1 unrouted)
N$118  (1 unrouted)
N$120  (1 unrouted)
N$121  (2 unrouted)
N$122  (1 unrouted)
N$123
  Bottom 0.406: LED6.K R11.1
N$124  (1 unrouted)
N$129  (1 unrouted)
N$137  (1 unrouted)
N$142  (1 unrouted)
N$143  (1 unrouted)
N$144  (1 unrouted)
N$146  (1 unrouted)
N$147  (1 unrouted)
N$155  (1 unrouted)
N$168  (2 unrouted)
N$169  (1 unrouted)
N$187  (1 unrouted)
N$188  (1 unrouted)
N$189  (1 unrouted)
N$190  (1 unrouted)
N$191  (1 unrouted)
N$192  (1 unrouted)
NINVX  (2 unrouted)
NINVY  (2 unrouted)
NORMALX  (4 unrouted)
NORMALY  (4 unrouted)
OFFDRAWSPEED  (2 unrouted)
P1  (3 unrouted)
P2  (3 unrouted)
P3  (3 unrouted)
PROCESSOROVERRIDE  (1 unrouted)
RESETVRAMPC  (1 unrouted)
ROTATE  (2 unrouted)
ROTCLK  (6 unrouted)
ROTMODE  (6 unrouted)
SHCON  (6 unrouted)
SUBTRACT  (1 unrouted)
U/DX  (3 unrouted)
U/DY  (3 unrouted)
VCC  (via drill 0.55)  (4 unrouted)
  Top 1.016: 83.82,288.29 v83.82,284.48 | 102.87,288.29 104.14,287.02 v104.14,284.48 | 123.19,288.29 124.46,287.02 v124.46,284.48 | 144.78,288.29 v144.78,284.48 | 165.1,288.29 v165.1,284.48 | 185.42,288.29 v185.42,284.48 | 204.47,288.29 205.74,287.02 v205.74,284.48 | 226.06,288.29 v226.06,284.48 | 245.11,288.29 246.38,287.02 v246.38,284.48 | 266.7,288.29 v266.7,284.48
  Top 2.54: P1.2 9.91,185.42 P1.1 | X2.8 337.82,259.72 X2.7
  Top 5.08: 9.91,185.42 16.51,185.42 23.49,192.41 23.49,277.5 34.29,288.29 83.82,288.29 102.87,288.29 123.19,288.29 144.78,288.29 165.1,288.29 185.42,288.29 204.47,288.29 226.06,288.29 245.11,288.29 266.7,288.29 335.28,288.29 346.07,277.5 346.07,259.72 337.82,259.72
  Bottom 1.016: v83.82,284.48 83.82,279.4 | 83.82,279.4 1A.14 | 83.82,279.4 83.82,243.84 | 83.82,243.84 83.82,218.44 | 83.82,218.44 83.82,212.09 | 83.82,212.09 83.82,175.26 | 83.82,175.26 83.82,105.41 | 83.82,105.41 83.82,76.2 | 83.82,76.2 83.82,69.85 | 83.82,69.85 83.82,35.56 1H.20 | 1G.20 83.82,69.85 | C20.1 83.82,76.2 | 1F.20 83.82,105.41 | 1D.20 83.82,175.26 | 1C.20 83.82,212.09 | 1B.14 83.82,243.84 | v104.14,284.48 104.14,279.4 | 104.14,279.4 2A.14 | 104.14,279.4 104.14,243.84 | 104.14,243.84 104.14,218.44 | 104.14,218.44 104.14,212.09 | 104.14,212.09 104.14,199.39 | 104.14,199.39 104.14,172.72 | 104.14,172.72 104.14,163.83 | 104.14,163.83 104.14,140.97 | 104.14,140.97 104.14,128.27 | 104.14,128.27 104.14,101.6 | 104.14,101.6 104.14,92.71 | 104.14,92.71 104.14,76.2 | 104.14,76.2 104.14,69.85 | 104.14,69.85 104.14,57.15 | 104.14,57.15 104.14,30.48 | 104.14,30.48 2H.14 | 2G.20 104.14,69.85 | C21.1 104.14,76.2 | 2F.14 104.14,101.6 | 2E.20 104.14,140.97 | 2D.14 104.14,172.72 | 2C.20 104.14,212.09 | C11.1 104.14,218.44 | C10.1 83.82,218.44 | 2B.14 104.14,243.84 | v124.46,284.48 124.46,279.4 | 124.46,279.4 R1.1 | 124.46,279.4 3A.14 | 124.46,279.4 124.46,261.62 120.65,257.81 3B.14 | 104.14,199.39 3C.5 | 104.14,218.44 C12.1 | 104.14,163.83 3D.5 | 104.14,128.27 3E.5 | 104.14,92.71 3F.5 | C22.1 104.14,76.2 | 104.14,57.15 3G.5 | 3H.5 109.22,21.59 104.14,26.67 104.14,30.48 | 4A.16 144.78,280.67 | 144.78,280.67 v144.78,284.48 | 144.78,280.67 144.78,252.73 | 144.78,252.73 4B.24 | 144.78,252.73 139.7,247.65 139.7,215.9 | 139.7,215.9 C13.1 | 139.7,215.9 146.05,209.55 146.05,190.5 | 4G/4H.14 146.05,48.26 146.05,83.82 | 146.05,190.5 146.05,154.94 | 146.05,154.94 146.05,91.44 | 146.05,91.44 146.05,83.82
  Bottom 1.016: 4F/4G.14 146.05,83.82 | C23.1 146.05,91.44 | 4D/4E.14 146.05,154.94 | 4C/4D.14 146.05,190.5 | v165.1,284.48 165.1,279.4 | 165.1,279.4 5A.14 | 165.1,279.4 165.1,243.84 | 165.1,243.84 165.1,218.44 | 165.1,218.44 165.1,209.55 | 165.1,209.55 165.1,173.99 | 165.1,173.99 165.1,138.43 | 165.1,138.43 165.1,102.87 | 165.1,102.87 165.1,76.2 | 165.1,76.2 165.1,67.31 | 165.1,67.31 165.1,31.75 5H.16 | 5G.16 165.1,67.31 | C24.1 165.1,76.2 | 5F.16 165.1,102.87 | 5E.16 165.1,138.43 | 5D.16 165.1,173.99 | 5C.16 165.1,209.55 | C14.1 165.1,218.44 | 5B.14 165.1,243.84 | v185.42,284.48 185.42,279.4 | 185.42,279.4 6A.14 | 185.42,279.4 185.42,243.84 | 185.42,243.84 185.42,218.44 | 185.42,218.44 185.42,209.55 | 185.42,209.55 185.42,173.99 | 185.42,173.99 185.42,138.43 | 185.42,138.43 185.42,102.87 | 185.42,102.87 185.42,76.2 | 185.42,76.2 185.42,67.31 | 185.42,67.31 185.42,31.75 6H.16 | 6G.16 185.42,67.31 | C55.1 185.42,76.2 | 6F.16 185.42,102.87 | 6E.16 185.42,138.43 | 6D.16 185.42,173.99 | 6C.16 185.42,209.55 | C15.1 185.42,218.44 | B6.14 185.42,243.84 | v205.74,284.48 205.74,279.4 | 205.74,279.4 7A.14 | 205.74,279.4 205.74,243.84 | 205.74,243.84 205.74,218.44 | 205.74,218.44 205.74,208.28 | 205.74,208.28 205.74,172.72 | 205.74,172.72 205.74,137.16 | 205.74,137.16 205.74,101.6 | 205.74,101.6 205.74,76.2 | 205.74,76.2 205.74,66.04 | 205.74,66.04 205.74,30.48 7H.14 | 7G.14 205.74,66.04 | C56.1 205.74,76.2 | 7F.14 205.74,101.6 | 7E.14 205.74,137.16 | 7D.14 205.74,172.72 | 7C.14 205.74,208.28 | C16.1 205.74,218.44 | 7B.14 205.74,243.84 | v226.06,284.48 226.06,279.4 | 226.06,279.4 8A.14 | R3.1 226.06,85.09 | 226.06,279.4 226.06,243.84 | 226.06,243.84 226.06,218.44 | 226.06,218.44 226.06,191.77 | 226.06,191.77 226.06,156.21
  Bottom 1.016: 226.06,156.21 226.06,92.71 | 226.06,92.71 226.06,85.09 | 226.06,85.09 8F/8G.16 | C57.1 226.06,92.71 | 226.06,85.09 226.06,49.53 8G/8H.16 | 8D/8E.16 226.06,156.21 | 8C/8D.16 226.06,191.77 | 226.06,191.77 R2.1 | C17.1 226.06,218.44 | 8B.14 226.06,243.84 | 9A.14 246.38,279.4 | 246.38,279.4 v246.38,284.48 | 246.38,279.4 246.38,243.84 | 246.38,243.84 9B.14 | 246.38,243.84 246.38,218.44 | 246.38,218.44 246.38,209.55 | 246.38,209.55 246.38,173.99 | 246.38,173.99 246.38,138.43 | 246.38,138.43 246.38,102.87 | 246.38,102.87 246.38,76.2 | 246.38,76.2 246.38,67.31 | 246.38,67.31 246.38,31.75 9H.16 | 9G.16 246.38,67.31 | C58.1 246.38,76.2 | 9F.16 246.38,102.87 | 9E.16 246.38,138.43 | 9D.16 246.38,173.99 | 9C.16 246.38,209.55 | C18.1 246.38,218.44 | 10C.16 266.7,209.55 | 266.7,209.55 266.7,218.44 | v266.7,284.48 266.7,269.57 | 266.7,269.57 266.7,218.44 | C19.1 266.7,218.44 | 266.7,209.55 266.7,173.99 | 266.7,173.99 266.7,138.43 | 266.7,138.43 266.7,102.87 | 266.7,102.87 266.7,76.2 | 266.7,76.2 266.7,67.31 | 266.7,67.31 266.7,31.75 10H.16 | 10G.16 266.7,67.31 | C59.1 266.7,76.2 | 10D.16 266.7,173.99 | 10E.16 266.7,138.43 | 10F.16 266.7,102.87 | 266.7,269.57 261.31,269.57 R9.2
  Bottom 2.54: P1.1 P1.2
VECTORCOMPLETE  (1 unrouted)
VRAM0  (3 unrouted)
VRAM1  (3 unrouted)
VRAM2  (3 unrouted)
VRAM3  (3 unrouted)
VRAM4  (2 unrouted)
VRAM5  (2 unrouted)
VRAM6  (2 unrouted)
VRAM7  (3 unrouted)
VRAM8  (2 unrouted)
VRAM9  (2 unrouted)
VRAM10  (2 unrouted)
VRAM11  (2 unrouted)
VRAMPC  (1 unrouted)
XBRM0  (1 unrouted)
XBRM1  (1 unrouted)
XBRM2  (1 unrouted)
XBRM3  (2 unrouted)
XBRM4  (1 unrouted)
XBRM5  (1 unrouted)
XBRM6  (1 unrouted)
XBRM7  (2 unrouted)
XBRM8  (1 unrouted)
XBRM9  (1 unrouted)
XBRM10  (1 unrouted)
XBRM11  (2 unrouted)
XBRMRATE  (1 unrouted)
XCUR0  (2 unrouted)
XCUR1  (2 unrouted)
XCUR2  (2 unrouted)
XCUR3  (2 unrouted)
XCUR4  (2 unrouted)
XCUR5  (2 unrouted)
XCUR6  (2 unrouted)
XCUR7  (2 unrouted)
XCUR8  (2 unrouted)
XCUR9  (2 unrouted)
XCUR10  (2 unrouted)
XCUR11  (2 unrouted)
XEND0  (4 unrouted)
  Top 0.432: 1C.19 2C.2
XEND1  (4 unrouted)
  Top 0.432: 2C.3 1C.18
XEND2  (4 unrouted)
  Top 0.432: 1C.17 2C.4
XEND3  (4 unrouted)
  Top 0.432: 2C.5 1C.16
XEND4  (4 unrouted)
  Top 0.432: 1C.15 2C.6
XEND5  (4 unrouted)
  Top 0.432: 2C.7 1C.14
XEND6  (4 unrouted)
  Top 0.432: 1C.13 2C.8
XEND7  (4 unrouted)
  Top 0.432: 2C.9 1C.12
XEND8  (5 unrouted)
XEND9  (5 unrouted)
XEND10  (5 unrouted)
XEND11  (5 unrouted)
XOUT  (4 unrouted)
XRATE  (3 unrouted)
YBRM0  (1 unrouted)
YBRM1  (1 unrouted)
YBRM2  (1 unrouted)
YBRM3  (2 unrouted)
YBRM4  (1 unrouted)
YBRM5  (1 unrouted)
YBRM6  (1 unrouted)
YBRM7  (2 unrouted)
YBRM8  (1 unrouted)
YBRM9  (1 unrouted)
YBRM10  (1 unrouted)
YBRM11  (2 unrouted)
YBRMRATE  (1 unrouted)
YCUR0  (2 unrouted)
YCUR1  (2 unrouted)
YCUR2  (2 unrouted)
YCUR3  (2 unrouted)
YCUR4  (2 unrouted)
YCUR5  (2 unrouted)
YCUR6  (2 unrouted)
YCUR7  (2 unrouted)
YCUR8  (2 unrouted)
YCUR9  (2 unrouted)
YCUR10  (2 unrouted)
YCUR11  (2 unrouted)
YEND0  (5 unrouted)
YEND1  (5 unrouted)
YEND2  (5 unrouted)
YEND3  (5 unrouted)
YEND4  (4 unrouted)
  Top 0.432: 1G.19 2G.2
YEND5  (4 unrouted)
  Top 0.432: 1G.18 2G.3
YEND6  (4 unrouted)
  Top 0.432: 2G.4 1G.17
YEND7  (4 unrouted)
  Top 0.432: 1G.16 2G.5
YEND8  (4 unrouted)
  Top 0.432: 2G.6 1G.15
YEND9  (4 unrouted)
  Top 0.432: 1G.14 2G.7
YEND10  (4 unrouted)
  Top 0.432: 2G.8 1G.13
YEND11  (4 unrouted)
  Top 0.432: 1G.12 2G.9
YOUT  (4 unrouted)
YRATE  (3 unrouted)
ZLD  (1 unrouted)
ZOUT  (2 unrouted)

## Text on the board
tPlace: Power Supply | -15V | -8V | +8V | +15V | +5V / LOGIC | 5V / DAC | A | Note: The analog circuits on this board / were NOT designed by Kincaid Arcade; / they were copied from the Atari Asteroids / Deluxe Manual. This project is intended / ONLY as a hobbyist's attempt to make a / vector arcade game, and neither Alexander / Haley nor Kincaid Arcade claim copyright or / ownership on any of the analog circuits. | 8 | Kincaid Arcade / Vector Graphics Card / REV - B | (c) Kincaid Arcade / 6/10/2020 / KincaidArcade.com | 1 | 2 | 3 | 4 | 5 | 6 | 7 | 8 | 9 | Power Input | Digital Circuits / Designed By: | Alexander K. Haley / (A 17 year old!) | B | 1 | All of the digital circuits in this design are licensed / under the Creative Commons License / CC BY-SA 4.0 | https://creativecommons.org/licenses/by-sa/4.0/ | 10 | C | X Analog Circuitry | D | X Gain | Sample & Hold | 6 | E | To Monitor | 1 | F | Y Analog Circuitry | Y Gain | G | H | Z-Amp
